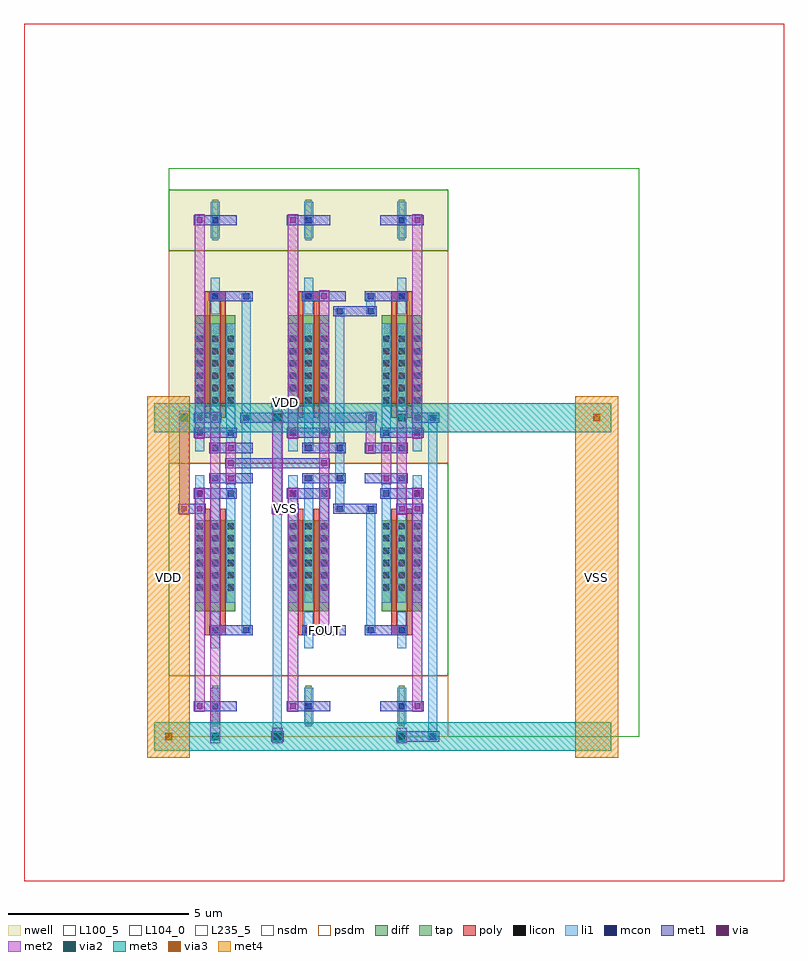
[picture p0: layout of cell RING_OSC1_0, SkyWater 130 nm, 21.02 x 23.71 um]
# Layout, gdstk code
from math import pi, radians
import gdstk
lib = gdstk.Library(unit=1e-6, precision=1e-09)
def R(c, l, rs):  # rectangles x0, y0, x1, y1
    for r in rs: c.add(gdstk.rectangle(r[:2], r[2:], *l))
def A(c, l, x, y, w, h, nx, ny, dx, dy):  # array of equal rectangles
    R(c, l, [(x+i*dx, y+j*dy, x+i*dx+w, y+j*dy+h) for i in range(nx) for j in range(ny)])
def P(c, l, *ps):  # polygons
    for p in ps: c.add(gdstk.Polygon(p, *l))
nwell = (64, 20)
diff = (65, 20)
tap = (65, 44)
poly = (66, 20)
licon = (66, 44)
li1 = (67, 20)
mcon = (67, 44)
met1 = (68, 20)
via = (68, 44)
met2 = (69, 20)
via2 = (69, 44)
met3 = (70, 20)
via3 = (70, 44)
met4 = (71, 20)
nsdm = (93, 44)
psdm = (94, 20)
L100_5 = (100, 5)
L104_0 = (104, 0)
L235_5 = (235, 5)

nmos_s_42092372_x1_y1_16 = lib.new_cell('NMOS_S_42092372_X1_Y1_1679678942_1679678944')
R(nmos_s_42092372_x1_y1_16, diff, [(0.735,1.575,1.845,4.095)])
R(nmos_s_42092372_x1_y1_16, tap, [(1.205,6.16,1.375,7.28)])
R(nmos_s_42092372_x1_y1_16, poly, [(1,1.26,1.15,4.62), (1.43,1.26,1.58,4.62), (1,4.485,1.58,4.755)])
A(nmos_s_42092372_x1_y1_16, licon, 0.775, 1.655, 0.17, 0.17, 3, 6, 0.43, 0.34)
R(nmos_s_42092372_x1_y1_16, licon, [(1.205,4.535,1.375,4.705), (1.205,6.635,1.375,6.805)])
A(nmos_s_42092372_x1_y1_16, li1, 0.735, 0.335, 0.25, 3.53, 3, 1, 0.43, 0)
R(nmos_s_42092372_x1_y1_16, li1, [(1.165,4.115,1.415,5.125), (1.165,6.215,1.415,7.225)])
R(nmos_s_42092372_x1_y1_16, mcon, [(1.205,0.335,1.375,0.505), (0.775,0.755,0.945,0.925), (1.635,0.755,1.805,0.925), (1.205,4.535,1.375,4.705), (1.205,6.635,1.375,6.805)])
R(nmos_s_42092372_x1_y1_16, met1, [(0.26,0.28,1.46,0.56), (0.69,0.7,1.89,0.98), (0.26,4.48,1.46,4.76), (0.69,6.58,1.89,6.86)])
R(nmos_s_42092372_x1_y1_16, via, [(1.645,0.765,1.795,0.915), (1.645,6.645,1.795,6.795)])
R(nmos_s_42092372_x1_y1_16, met2, [(1.58,0.68,1.86,6.88)])
R(nmos_s_42092372_x1_y1_16, nsdm, [(0,0,2.58,5.88)])
R(nmos_s_42092372_x1_y1_16, psdm, [(0,5.88,2.58,7.56)])
R(nmos_s_42092372_x1_y1_16, L100_5, [(0,0,2.58,7.56)])

pmos_s_45039047_x1_y1_16 = lib.new_cell('PMOS_S_45039047_X1_Y1_1679678943_1679678944')
R(pmos_s_45039047_x1_y1_16, nwell, [(0,0,2.58,7.56)])
R(pmos_s_45039047_x1_y1_16, diff, [(0.735,1.575,1.845,4.095)])
R(pmos_s_45039047_x1_y1_16, tap, [(1.205,6.16,1.375,7.28)])
R(pmos_s_45039047_x1_y1_16, poly, [(1,1.26,1.15,4.62), (1.43,1.26,1.58,4.62), (1,4.485,1.58,4.755)])
A(pmos_s_45039047_x1_y1_16, licon, 0.775, 1.655, 0.17, 0.17, 3, 6, 0.43, 0.34)
R(pmos_s_45039047_x1_y1_16, licon, [(1.205,4.535,1.375,4.705), (1.205,6.635,1.375,6.805)])
A(pmos_s_45039047_x1_y1_16, li1, 0.735, 0.335, 0.25, 3.53, 3, 1, 0.43, 0)
R(pmos_s_45039047_x1_y1_16, li1, [(1.165,4.115,1.415,5.125), (1.165,6.215,1.415,7.225)])
R(pmos_s_45039047_x1_y1_16, mcon, [(1.205,0.335,1.375,0.505), (0.775,0.755,0.945,0.925), (1.635,0.755,1.805,0.925), (1.205,4.535,1.375,4.705), (1.205,6.635,1.375,6.805)])
R(pmos_s_45039047_x1_y1_16, met1, [(0.26,0.28,1.46,0.56), (0.69,0.7,1.89,0.98), (0.26,4.48,1.46,4.76), (0.69,6.58,1.89,6.86)])
R(pmos_s_45039047_x1_y1_16, via, [(1.645,0.765,1.795,0.915), (1.645,6.645,1.795,6.795)])
R(pmos_s_45039047_x1_y1_16, met2, [(1.58,0.68,1.86,6.88)])
R(pmos_s_45039047_x1_y1_16, nsdm, [(0,5.88,2.58,7.56)])
R(pmos_s_45039047_x1_y1_16, psdm, [(0,0,2.58,5.88)])
R(pmos_s_45039047_x1_y1_16, L100_5, [(0,0,2.58,7.56)])

stage2_inv_89403287_pg0_ = lib.new_cell('STAGE2_INV_89403287_PG0_0_0_1679678944')
R(stage2_inv_89403287_pg0_, li1, [(2.025,2.855,2.275,3.025), (2.025,2.855,2.275,3.025), (2.025,2.855,2.275,3.025), (2.025,2.855,2.275,3.025), (2.025,2.855,2.275,3.025), (2.025,2.855,2.275,3.025), (2.025,2.94,2.275,6.3), (2.025,6.215,2.275,6.385), (2.025,6.215,2.275,6.385), (2.025,6.215,2.275,6.385), (2.025,6.215,2.275,6.385), (2.025,6.215,2.275,6.385), (2.025,6.215,2.275,6.385), (2.885,6.215,3.135,6.385), (2.885,6.215,3.135,6.385), (2.885,6.215,3.135,6.385), (2.885,6.215,3.135,6.385), (2.885,6.215,3.135,6.385), (2.885,6.215,3.135,6.385), (2.885,6.3,3.135,7.14), (2.885,7.055,3.135,7.225), (2.885,7.055,3.135,7.225), (2.885,7.055,3.135,7.225), (2.885,7.055,3.135,7.225), (2.885,7.055,3.135,7.225), (2.885,7.055,3.135,7.225), (2.885,7.14,3.135,7.98), (2.885,7.895,3.135,8.065), (2.885,7.895,3.135,8.065), (2.885,7.895,3.135,8.065), (2.885,7.895,3.135,8.065), (2.885,7.98,3.135,11.76), (2.025,11.675,2.275,11.845), (2.025,11.675,2.275,11.845), (2.885,11.675,3.135,11.845), (2.885,11.675,3.135,11.845), (2.025,11.76,2.275,12.18), (2.025,12.095,2.275,12.265), (2.025,12.095,2.275,12.265)])
R(stage2_inv_89403287_pg0_, mcon, [(2.065,2.855,2.235,3.025), (2.065,2.855,2.235,3.025), (2.065,2.855,2.235,3.025), (2.065,2.855,2.235,3.025), (2.065,2.855,2.235,3.025), (2.065,2.855,2.235,3.025), (2.065,6.215,2.235,6.385), (2.065,6.215,2.235,6.385), (2.065,6.215,2.235,6.385), (2.065,6.215,2.235,6.385), (2.065,6.215,2.235,6.385), (2.065,6.215,2.235,6.385), (2.925,6.215,3.095,6.385), (2.925,6.215,3.095,6.385), (2.925,6.215,3.095,6.385), (2.925,6.215,3.095,6.385), (2.925,6.215,3.095,6.385), (2.925,6.215,3.095,6.385), (2.925,7.055,3.095,7.225), (2.925,7.055,3.095,7.225), (2.925,7.055,3.095,7.225), (2.925,7.055,3.095,7.225), (2.925,7.055,3.095,7.225), (2.925,7.055,3.095,7.225), (2.925,7.895,3.095,8.065), (2.925,7.895,3.095,8.065), (2.925,7.895,3.095,8.065), (2.925,7.895,3.095,8.065), (2.065,11.675,2.235,11.845), (2.065,11.675,2.235,11.845), (2.925,11.675,3.095,11.845), (2.925,11.675,3.095,11.845), (2.065,12.095,2.235,12.265), (2.065,12.095,2.235,12.265)])
R(stage2_inv_89403287_pg0_, met1, [(1.98,2.8,2.32,3.08), (1.98,2.8,2.32,3.08), (1.98,2.8,2.32,3.08), (1.98,2.8,2.32,3.08), (1.98,2.8,2.32,3.08), (1.98,2.8,2.32,3.08), (3.28,2.8,3.6,3.08), (3.28,2.8,3.6,3.08), (1.98,6.16,2.32,6.44), (1.98,6.16,2.32,6.44), (1.98,6.16,2.32,6.44), (1.98,6.16,2.32,6.44), (1.98,6.16,2.32,6.44), (1.98,6.16,2.32,6.44), (2.15,6.16,3.01,6.44), (2.84,6.16,3.18,6.44), (2.84,6.16,3.18,6.44), (2.84,6.16,3.18,6.44), (2.84,6.16,3.18,6.44), (2.84,6.16,3.18,6.44), (2.84,6.16,3.18,6.44), (1.56,7,1.88,7.28), (1.56,7,1.88,7.28), (2.84,7,3.18,7.28), (2.84,7,3.18,7.28), (2.84,7,3.18,7.28), (2.84,7,3.18,7.28), (2.84,7,3.18,7.28), (2.84,7,3.18,7.28), (1.56,7.84,1.88,8.12), (1.56,7.84,1.88,8.12), (2.84,7.84,3.18,8.12), (2.84,7.84,3.18,8.12), (2.84,7.84,3.18,8.12), (2.84,7.84,3.18,8.12), (1.98,11.62,2.32,11.9), (1.98,11.62,2.32,11.9), (2.15,11.62,3.01,11.9), (2.84,11.62,3.18,11.9), (2.84,11.62,3.18,11.9), (1.98,12.04,2.32,12.32), (1.98,12.04,2.32,12.32), (3.28,12.04,3.6,12.32), (3.28,12.04,3.6,12.32)])
P(stage2_inv_89403287_pg0_, met1, [(0,0),(0,0),(0,0),(0,0)],
  [(0,0),(0,0),(0,0),(0,0)],
  [(0,0),(0,0),(0,0),(0,0)],
  [(0,0),(0,0),(0,0),(0,0)],
  [(0,0),(0,0),(0,0),(0,0)],
  [(0,0),(0,0),(0,0),(0,0)],
  [(0,0),(0,0),(0,0),(0,0)],
  [(0,0),(0,0),(0,0),(0,0)])
R(stage2_inv_89403287_pg0_, via, [(3.365,2.865,3.515,3.015), (3.365,2.865,3.515,3.015), (1.645,7.065,1.795,7.215), (1.645,7.065,1.795,7.215), (1.645,7.905,1.795,8.055), (1.645,7.905,1.795,8.055), (3.365,12.105,3.515,12.255), (3.365,12.105,3.515,12.255)])
R(stage2_inv_89403287_pg0_, met2, [(3.3,2.78,3.58,3.1), (3.3,2.78,3.58,3.1), (3.3,2.94,3.58,12.18), (1.58,6.98,1.86,7.3), (1.58,6.98,1.86,7.3), (1.58,7.14,1.86,7.98), (1.58,7.82,1.86,8.14), (1.58,7.82,1.86,8.14), (3.3,12.02,3.58,12.34), (3.3,12.02,3.58,12.34)])
P(stage2_inv_89403287_pg0_, met2, [(0,0),(0,0),(0,0),(0,0)],
  [(0,0),(0,0),(0,0),(0,0)],
  [(0,0),(0,0),(0,0),(0,0)],
  [(0,0),(0,0),(0,0),(0,0)])
R(stage2_inv_89403287_pg0_, L235_5, [(0,0,5.16,15.12)])
stage2_inv_89403287_pg0_.add(gdstk.Reference(nmos_s_42092372_x1_y1_16, (2.58,7.56), x_reflection=True))
stage2_inv_89403287_pg0_.add(gdstk.Reference(nmos_s_42092372_x1_y1_16, (2.58,7.56), rotation=pi))
stage2_inv_89403287_pg0_.add(gdstk.Reference(pmos_s_45039047_x1_y1_16, (2.58,7.56)))
stage2_inv_89403287_pg0_.add(gdstk.Reference(pmos_s_45039047_x1_y1_16, (2.58,7.56), rotation=pi, x_reflection=True))

c_nmos_s_42092372_x1_y1_16 = lib.new_cell('NMOS_S_42092372_X1_Y1_1679678942_1679678943')
R(c_nmos_s_42092372_x1_y1_16, diff, [(0.735,1.575,1.845,4.095)])
R(c_nmos_s_42092372_x1_y1_16, tap, [(1.205,6.16,1.375,7.28)])
R(c_nmos_s_42092372_x1_y1_16, poly, [(1,1.26,1.15,4.62), (1.43,1.26,1.58,4.62), (1,4.485,1.58,4.755)])
A(c_nmos_s_42092372_x1_y1_16, licon, 0.775, 1.655, 0.17, 0.17, 3, 6, 0.43, 0.34)
R(c_nmos_s_42092372_x1_y1_16, licon, [(1.205,4.535,1.375,4.705), (1.205,6.635,1.375,6.805)])
A(c_nmos_s_42092372_x1_y1_16, li1, 0.735, 0.335, 0.25, 3.53, 3, 1, 0.43, 0)
R(c_nmos_s_42092372_x1_y1_16, li1, [(1.165,4.115,1.415,5.125), (1.165,6.215,1.415,7.225)])
R(c_nmos_s_42092372_x1_y1_16, mcon, [(1.205,0.335,1.375,0.505), (0.775,0.755,0.945,0.925), (1.635,0.755,1.805,0.925), (1.205,4.535,1.375,4.705), (1.205,6.635,1.375,6.805)])
R(c_nmos_s_42092372_x1_y1_16, met1, [(0.26,0.28,1.46,0.56), (0.69,0.7,1.89,0.98), (0.26,4.48,1.46,4.76), (0.69,6.58,1.89,6.86)])
R(c_nmos_s_42092372_x1_y1_16, via, [(1.645,0.765,1.795,0.915), (1.645,6.645,1.795,6.795)])
R(c_nmos_s_42092372_x1_y1_16, met2, [(1.58,0.68,1.86,6.88)])
R(c_nmos_s_42092372_x1_y1_16, nsdm, [(0,0,2.58,5.88)])
R(c_nmos_s_42092372_x1_y1_16, psdm, [(0,5.88,2.58,7.56)])
R(c_nmos_s_42092372_x1_y1_16, L100_5, [(0,0,2.58,7.56)])

c_pmos_s_45039047_x1_y1_16 = lib.new_cell('PMOS_S_45039047_X1_Y1_1679678943_1679678943')
R(c_pmos_s_45039047_x1_y1_16, nwell, [(0,0,2.58,7.56)])
R(c_pmos_s_45039047_x1_y1_16, diff, [(0.735,1.575,1.845,4.095)])
R(c_pmos_s_45039047_x1_y1_16, tap, [(1.205,6.16,1.375,7.28)])
R(c_pmos_s_45039047_x1_y1_16, poly, [(1,1.26,1.15,4.62), (1.43,1.26,1.58,4.62), (1,4.485,1.58,4.755)])
A(c_pmos_s_45039047_x1_y1_16, licon, 0.775, 1.655, 0.17, 0.17, 3, 6, 0.43, 0.34)
R(c_pmos_s_45039047_x1_y1_16, licon, [(1.205,4.535,1.375,4.705), (1.205,6.635,1.375,6.805)])
A(c_pmos_s_45039047_x1_y1_16, li1, 0.735, 0.335, 0.25, 3.53, 3, 1, 0.43, 0)
R(c_pmos_s_45039047_x1_y1_16, li1, [(1.165,4.115,1.415,5.125), (1.165,6.215,1.415,7.225)])
R(c_pmos_s_45039047_x1_y1_16, mcon, [(1.205,0.335,1.375,0.505), (0.775,0.755,0.945,0.925), (1.635,0.755,1.805,0.925), (1.205,4.535,1.375,4.705), (1.205,6.635,1.375,6.805)])
R(c_pmos_s_45039047_x1_y1_16, met1, [(0.26,0.28,1.46,0.56), (0.69,0.7,1.89,0.98), (0.26,4.48,1.46,4.76), (0.69,6.58,1.89,6.86)])
R(c_pmos_s_45039047_x1_y1_16, via, [(1.645,0.765,1.795,0.915), (1.645,6.645,1.795,6.795)])
R(c_pmos_s_45039047_x1_y1_16, met2, [(1.58,0.68,1.86,6.88)])
R(c_pmos_s_45039047_x1_y1_16, nsdm, [(0,5.88,2.58,7.56)])
R(c_pmos_s_45039047_x1_y1_16, psdm, [(0,0,2.58,5.88)])
R(c_pmos_s_45039047_x1_y1_16, L100_5, [(0,0,2.58,7.56)])

inv_38424460_pg0_0_0_167 = lib.new_cell('INV_38424460_PG0_0_0_1679678943')
R(inv_38424460_pg0_0_0_167, li1, [(0.305,2.855,0.555,3.025), (0.305,2.855,0.555,3.025), (0.305,2.94,0.555,12.18), (0.305,12.095,0.555,12.265), (0.305,12.095,0.555,12.265)])
R(inv_38424460_pg0_0_0_167, mcon, [(0.345,2.855,0.515,3.025), (0.345,2.855,0.515,3.025), (0.345,12.095,0.515,12.265), (0.345,12.095,0.515,12.265)])
R(inv_38424460_pg0_0_0_167, met1, [(0.26,2.8,0.6,3.08), (0.26,2.8,0.6,3.08), (0.7,7,1.02,7.28), (0.7,7,1.02,7.28), (0.7,7.84,1.02,8.12), (0.7,7.84,1.02,8.12), (0.26,12.04,0.6,12.32), (0.26,12.04,0.6,12.32)])
P(inv_38424460_pg0_0_0_167, met1, [(0,0),(0,0),(0,0),(0,0)],
  [(0,0),(0,0),(0,0),(0,0)],
  [(0,0),(0,0),(0,0),(0,0)],
  [(0,0),(0,0),(0,0),(0,0)])
R(inv_38424460_pg0_0_0_167, via, [(0.785,7.065,0.935,7.215), (0.785,7.065,0.935,7.215), (0.785,7.905,0.935,8.055), (0.785,7.905,0.935,8.055)])
R(inv_38424460_pg0_0_0_167, met2, [(0.72,6.98,1,7.3), (0.72,6.98,1,7.3), (0.72,7.14,1,7.98), (0.72,7.82,1,8.14), (0.72,7.82,1,8.14)])
P(inv_38424460_pg0_0_0_167, met2, [(0,0),(0,0),(0,0),(0,0)],
  [(0,0),(0,0),(0,0),(0,0)])
R(inv_38424460_pg0_0_0_167, L235_5, [(0,0,2.58,15.12)])
inv_38424460_pg0_0_0_167.add(gdstk.Reference(c_nmos_s_42092372_x1_y1_16, (0,7.56), x_reflection=True))
inv_38424460_pg0_0_0_167.add(gdstk.Reference(c_pmos_s_45039047_x1_y1_16, (0,7.56)))

ring_osc1_0 = lib.new_cell('RING_OSC1_0')
R(ring_osc1_0, li1, [(2.885,-0.085,3.135,0.085), (7.185,-0.085,7.435,0.085), (7.185,-0.085,7.435,0.085), (7.185,-0.085,7.435,0.085), (2.885,0,3.135,9.24), (7.185,0,7.435,8.82), (2.025,8.735,2.275,8.905), (2.025,8.735,2.275,8.905), (7.185,8.735,7.435,8.905), (7.185,8.735,7.435,8.905), (7.185,8.735,7.435,8.905), (2.885,9.155,3.135,9.325), (2.885,9.155,3.135,9.325), (2.885,9.155,3.135,9.325), (2.885,9.155,3.135,9.325)])
P(ring_osc1_0, li1, [(0,0),(0,0),(0,0),(0,0)])
R(ring_osc1_0, mcon, [(2.925,-0.085,3.095,0.085), (7.225,-0.085,7.395,0.085), (7.225,-0.085,7.395,0.085), (7.225,-0.085,7.395,0.085), (2.065,8.735,2.235,8.905), (2.065,8.735,2.235,8.905), (7.225,8.735,7.395,8.905), (7.225,8.735,7.395,8.905), (7.225,8.735,7.395,8.905), (2.925,9.155,3.095,9.325), (2.925,9.155,3.095,9.325), (2.925,9.155,3.095,9.325), (2.925,9.155,3.095,9.325)])
R(ring_osc1_0, met1, [(2.84,-0.14,3.18,0.14), (2.85,-0.14,3.17,0.14), (2.861,-0.14,3.159,0.14), (6.29,-0.14,6.61,0.14), (6.29,-0.14,6.61,0.14), (6.29,-0.14,6.61,0.14), (6.45,-0.14,7.31,0.14), (7.14,-0.14,7.48,0.14), (7.14,-0.14,7.48,0.14), (7.14,-0.14,7.48,0.14), (0.27,6.16,0.59,6.44), (0.27,6.16,0.59,6.44), (0.43,6.16,0.86,6.44), (0.7,6.16,1.02,6.44), (0.7,6.16,1.02,6.44), (2.85,6.16,3.17,6.44), (2.85,6.16,3.17,6.44), (2.85,6.16,3.17,6.44), (2.85,6.16,3.17,6.44), (3.01,6.16,3.44,6.44), (3.28,6.16,3.6,6.44), (3.28,6.16,3.6,6.44), (3.28,6.16,3.6,6.44), (3.28,6.16,3.6,6.44), (6.29,6.16,6.61,6.44), (6.29,6.16,6.61,6.44), (6.29,6.16,6.61,6.44), (6.45,6.16,6.88,6.44), (6.72,6.16,7.04,6.44), (6.72,6.16,7.04,6.44), (6.72,6.16,7.04,6.44), (1.56,7.42,1.88,7.7), (1.56,7.42,1.88,7.7), (1.72,7.42,4.3,7.7), (4.14,7.42,4.46,7.7), (4.14,7.42,4.46,7.7), (5.43,7.84,5.75,8.12), (5.43,7.84,5.75,8.12), (0.7,8.68,1.02,8.96), (0.7,8.68,1.02,8.96), (0.86,8.68,1.29,8.96), (1.13,8.68,1.45,8.96), (1.13,8.68,1.45,8.96), (1.98,8.68,2.32,8.96), (1.98,8.68,2.32,8.96), (2.15,8.68,5.59,8.96), (5.43,8.68,5.75,8.96), (5.43,8.68,5.75,8.96), (6.72,8.68,7.04,8.96), (6.72,8.68,7.04,8.96), (6.72,8.68,7.04,8.96), (6.88,8.68,7.31,8.96), (7.14,8.68,7.48,8.96), (7.14,8.68,7.48,8.96), (7.14,8.68,7.48,8.96), (2.84,9.1,3.18,9.38), (2.84,9.1,3.18,9.38), (2.84,9.1,3.18,9.38), (2.84,9.1,3.18,9.38), (3.01,9.1,3.44,9.38), (3.28,9.1,3.6,9.38), (3.28,9.1,3.6,9.38), (3.28,9.1,3.6,9.38), (3.28,9.1,3.6,9.38)])
P(ring_osc1_0, met1, [(0,0),(0,0),(0,0),(0,0)],
  [(0,0),(0,0),(0,0),(0,0)],
  [(0,0),(0,0),(0,0),(0,0)],
  [(0,0),(0,0),(0,0),(0,0)],
  [(0,0),(0,0),(0,0),(0,0)],
  [(0,0),(0,0),(0,0),(0,0)],
  [(0,0),(0,0),(0,0),(0,0)],
  [(0,0),(0,0),(0,0),(0,0)],
  [(0,0),(0,0),(0,0),(0,0)],
  [(0,0),(0,0),(0,0),(0,0)],
  [(0,0),(0,0),(0,0),(0,0)],
  [(0,0),(0,0),(0,0),(0,0)],
  [(0,0),(0,0),(0,0),(0,0)],
  [(0,0),(0,0),(0,0),(0,0)],
  [(0,0),(0,0),(0,0),(0,0)],
  [(0,0),(0,0),(0,0),(0,0)],
  [(0,0),(0,0),(0,0),(0,0)])
R(ring_osc1_0, via, [(2.935,-0.075,3.085,0.075), (6.375,-0.075,6.525,0.075), (6.375,-0.075,6.525,0.075), (6.375,-0.075,6.525,0.075), (0.355,6.225,0.505,6.375), (0.355,6.225,0.505,6.375), (0.785,6.225,0.935,6.375), (0.785,6.225,0.935,6.375), (2.935,6.225,3.085,6.375), (2.935,6.225,3.085,6.375), (2.935,6.225,3.085,6.375), (2.935,6.225,3.085,6.375), (3.365,6.225,3.515,6.375), (3.365,6.225,3.515,6.375), (3.365,6.225,3.515,6.375), (3.365,6.225,3.515,6.375), (6.375,6.225,6.525,6.375), (6.375,6.225,6.525,6.375), (6.375,6.225,6.525,6.375), (6.805,6.225,6.955,6.375), (6.805,6.225,6.955,6.375), (6.805,6.225,6.955,6.375), (1.645,7.485,1.795,7.635), (1.645,7.485,1.795,7.635), (4.225,7.485,4.375,7.635), (4.225,7.485,4.375,7.635), (5.515,7.905,5.665,8.055), (5.515,7.905,5.665,8.055), (0.785,8.745,0.935,8.895), (0.785,8.745,0.935,8.895), (1.215,8.745,1.365,8.895), (1.215,8.745,1.365,8.895), (5.515,8.745,5.665,8.895), (5.515,8.745,5.665,8.895), (6.805,8.745,6.955,8.895), (6.805,8.745,6.955,8.895), (6.805,8.745,6.955,8.895), (3.365,9.165,3.515,9.315), (3.365,9.165,3.515,9.315), (3.365,9.165,3.515,9.315), (3.365,9.165,3.515,9.315)])
R(ring_osc1_0, met2, [(1.15,-0.185,1.43,0.185), (1.15,-0.185,1.43,0.185), (2.87,-0.185,3.15,0.185), (2.87,-0.185,3.15,0.185), (2.87,-0.185,3.15,0.185), (2.87,-0.185,3.15,0.185), (6.31,-0.185,6.59,0.185), (6.31,-0.185,6.59,0.185), (6.31,-0.185,6.59,0.185), (2.87,-0.16,3.15,0.16), (6.31,-0.16,6.59,0.16), (6.31,-0.16,6.59,0.16), (6.31,-0.16,6.59,0.16), (1.15,0,1.43,8.82), (2.87,0,3.15,0.242), (6.31,0,6.59,0.242), (0.29,6.14,0.57,6.46), (0.29,6.14,0.57,6.46), (0.72,6.14,1,6.46), (0.72,6.14,1,6.46), (2.87,6.14,3.15,6.46), (2.87,6.14,3.15,6.46), (2.87,6.14,3.15,6.46), (2.87,6.14,3.15,6.46), (3.3,6.14,3.58,6.46), (3.3,6.14,3.58,6.46), (3.3,6.14,3.58,6.46), (3.3,6.14,3.58,6.46), (6.31,6.14,6.59,6.46), (6.31,6.14,6.59,6.46), (6.31,6.14,6.59,6.46), (6.74,6.14,7.02,6.46), (6.74,6.14,7.02,6.46), (6.74,6.14,7.02,6.46), (0.29,6.3,0.57,8.82), (2.87,6.3,3.15,8.82), (6.31,6.3,6.59,8.82), (1.58,7.4,1.86,7.72), (1.58,7.4,1.86,7.72), (4.16,7.4,4.44,7.72), (4.16,7.4,4.44,7.72), (5.45,7.82,5.73,8.14), (5.45,7.82,5.73,8.14), (5.45,7.98,5.73,8.82), (0.29,8.635,0.57,9.005), (0.29,8.635,0.57,9.005), (2.87,8.635,3.15,9.005), (2.87,8.635,3.15,9.005), (2.87,8.635,3.15,9.005), (2.87,8.635,3.15,9.005), (6.31,8.635,6.59,9.005), (6.31,8.635,6.59,9.005), (6.31,8.635,6.59,9.005), (0.72,8.66,1,8.98), (0.72,8.66,1,8.98), (1.15,8.66,1.43,8.98), (1.15,8.66,1.43,8.98), (5.45,8.66,5.73,8.98), (5.45,8.66,5.73,8.98), (6.74,8.66,7.02,8.98), (6.74,8.66,7.02,8.98), (6.74,8.66,7.02,8.98), (3.3,9.08,3.58,9.4), (3.3,9.08,3.58,9.4), (3.3,9.08,3.58,9.4), (3.3,9.08,3.58,9.4)])
P(ring_osc1_0, met2, [(0,0),(0,0),(0,0),(0,0)],
  [(0,0),(0,0),(0,0),(0,0)],
  [(0,0),(0,0),(0,0),(0,0)])
R(ring_osc1_0, via2, [(1.19,-0.1,1.39,0.1), (1.19,-0.1,1.39,0.1), (2.91,-0.1,3.11,0.1), (2.91,-0.1,3.11,0.1), (2.91,-0.1,3.11,0.1), (2.91,-0.1,3.11,0.1), (6.35,-0.1,6.55,0.1), (6.35,-0.1,6.55,0.1), (6.35,-0.1,6.55,0.1), (0.33,8.72,0.53,8.92), (0.33,8.72,0.53,8.92), (2.91,8.72,3.11,8.92), (2.91,8.72,3.11,8.92), (2.91,8.72,3.11,8.92), (2.91,8.72,3.11,8.92), (6.35,8.72,6.55,8.92), (6.35,8.72,6.55,8.92), (6.35,8.72,6.55,8.92)])
A(ring_osc1_0, met3, -0.4, -0.4, 4.24, 0.8, 3, 2, 3.44, 8.82)
R(ring_osc1_0, met3, [(-0.165,-0.4,0.165,0.4), (1.125,-0.4,1.455,0.4), (1.125,-0.4,1.455,0.4), (2.845,-0.4,3.175,0.4), (2.845,-0.4,3.175,0.4), (2.845,-0.4,3.175,0.4), (2.845,-0.4,3.175,0.4), (6.285,-0.4,6.615,0.4), (6.285,-0.4,6.615,0.4), (6.285,-0.4,6.615,0.4), (9.92,-0.4,12.24,0.4), (0.265,8.42,0.595,9.22), (0.265,8.42,0.595,9.22), (2.845,8.42,3.175,9.22), (2.845,8.42,3.175,9.22), (2.845,8.42,3.175,9.22), (2.845,8.42,3.175,9.22), (6.285,8.42,6.615,9.22), (6.285,8.42,6.615,9.22), (6.285,8.42,6.615,9.22), (9.92,8.42,12.24,9.22), (11.675,8.42,12.005,9.22)])
R(ring_osc1_0, via3, [(-0.1,-0.1,0.1,0.1), (11.74,8.72,11.94,8.92)])
R(ring_osc1_0, met4, [(-0.59,-0.59,0.59,9.41), (11.25,-0.59,12.43,9.41), (-0.59,-0.165,0.59,0.165), (11.25,8.655,12.43,8.985)])
R(ring_osc1_0, L104_0, [(-4,-4,17.02,19.71)])
R(ring_osc1_0, L235_5, [(0,0,13.02,15.71)])
ring_osc1_0.add(gdstk.Reference(stage2_inv_89403287_pg0_, (7.74,0), rotation=pi, x_reflection=True))
ring_osc1_0.add(gdstk.Reference(inv_38424460_pg0_0_0_167, (2.58,0), rotation=pi, x_reflection=True))
ring_osc1_0.add(gdstk.Label('FOUT', (4.3,2.94), layer=68, texttype=5))
ring_osc1_0.add(gdstk.Label('VSS', (11.84,4.41), layer=71, texttype=5))
ring_osc1_0.add(gdstk.Label('VSS', (3.225,6.3), layer=68, texttype=5))
ring_osc1_0.add(gdstk.Label('VSS', (11.84,4.41), layer=71, texttype=5))
ring_osc1_0.add(gdstk.Label('VSS', (11.84,4.41), layer=71, texttype=5))
ring_osc1_0.add(gdstk.Label('VSS', (11.84,4.41), layer=71, texttype=5))
ring_osc1_0.add(gdstk.Label('VSS', (11.84,4.41), layer=71, texttype=5))
ring_osc1_0.add(gdstk.Label('VSS', (11.84,4.41), layer=71, texttype=5))
ring_osc1_0.add(gdstk.Label('VSS', (11.84,4.41), layer=71, texttype=5))
ring_osc1_0.add(gdstk.Label('VSS', (11.84,4.41), layer=71, texttype=5))
ring_osc1_0.add(gdstk.Label('VSS', (11.84,4.41), layer=71, texttype=5))
ring_osc1_0.add(gdstk.Label('VSS', (11.84,4.41), layer=71, texttype=5))
ring_osc1_0.add(gdstk.Label('VSS', (11.84,4.41), layer=71, texttype=5))
ring_osc1_0.add(gdstk.Label('VSS', (11.84,4.41), layer=71, texttype=5))
ring_osc1_0.add(gdstk.Label('VDD', (0,4.41), layer=71, texttype=5))
ring_osc1_0.add(gdstk.Label('VDD', (3.225,9.24), layer=68, texttype=5))
ring_osc1_0.add(gdstk.Label('VDD', (0,4.41), layer=71, texttype=5))
ring_osc1_0.add(gdstk.Label('VDD', (0,4.41), layer=71, texttype=5))
ring_osc1_0.add(gdstk.Label('VDD', (0,4.41), layer=71, texttype=5))
ring_osc1_0.add(gdstk.Label('VDD', (0,4.41), layer=71, texttype=5))
ring_osc1_0.add(gdstk.Label('VDD', (0,4.41), layer=71, texttype=5))
ring_osc1_0.add(gdstk.Label('VDD', (0,4.41), layer=71, texttype=5))
ring_osc1_0.add(gdstk.Label('VDD', (0,4.41), layer=71, texttype=5))
ring_osc1_0.add(gdstk.Label('VDD', (0,4.41), layer=71, texttype=5))
ring_osc1_0.add(gdstk.Label('VDD', (0,4.41), layer=71, texttype=5))
ring_osc1_0.add(gdstk.Label('VDD', (0,4.41), layer=71, texttype=5))
ring_osc1_0.add(gdstk.Label('VDD', (0,4.41), layer=71, texttype=5))
ring_osc1_0.add(gdstk.Label('VDD', (0,4.41), layer=71, texttype=5))
ring_osc1_0.add(gdstk.Label('VDD', (0,4.41), layer=71, texttype=5))
ring_osc1_0.add(gdstk.Label('VDD', (0,4.41), layer=71, texttype=5))
ring_osc1_0.add(gdstk.Label('VDD', (0,4.41), layer=71, texttype=5))

lib.write_gds('RING_OSC1_0.gds')
